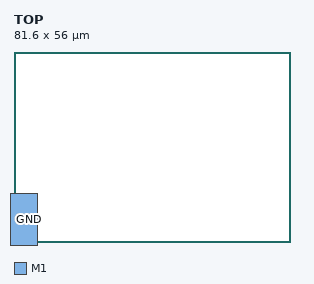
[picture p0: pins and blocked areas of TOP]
MACRO TOP
  CLASS CORE ;
  ORIGIN 0 0 ;
  SIZE 81.600 BY 56.000 ;
  SYMMETRY X Y ;
  SITE TR1um_site ;
  PIN GND
    DIRECTION INOUT ;
    USE GROUND ;
    PORT
      LAYER M1 ;
        RECT -1.000 -1.000 7.000 14.300 ;
    END
  END GND
END TOP
